VERSION 5.7 ;
  NOWIREEXTENSIONATPIN ON ;
  DIVIDERCHAR "/" ;
  BUSBITCHARS "[]" ;
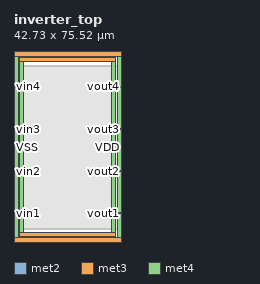
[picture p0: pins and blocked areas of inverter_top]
MACRO inverter_top
  CLASS BLOCK ;
  FOREIGN inverter_top ;
  ORIGIN 0.000 0.000 ;
  SIZE 42.730 BY 75.520 ;
  PIN vin1
    DIRECTION INPUT ;
    USE SIGNAL ;
    ANTENNAGATEAREA 60.000000 ;
    PORT
      LAYER met2 ;
        RECT 0.000 11.250 7.005 11.650 ;
    END
  END vin1
  PIN vout1
    DIRECTION OUTPUT ;
    USE SIGNAL ;
    ANTENNADIFFAREA 9.000000 ;
    PORT
      LAYER met2 ;
        RECT 32.750 11.250 42.730 11.650 ;
    END
  END vout1
  PIN vin2
    DIRECTION INPUT ;
    USE SIGNAL ;
    ANTENNAGATEAREA 60.000000 ;
    PORT
      LAYER met2 ;
        RECT 0.000 27.980 7.005 28.380 ;
    END
  END vin2
  PIN vout2
    DIRECTION OUTPUT ;
    USE SIGNAL ;
    ANTENNADIFFAREA 9.000000 ;
    PORT
      LAYER met2 ;
        RECT 32.750 27.980 42.730 28.380 ;
    END
  END vout2
  PIN vin3
    DIRECTION INPUT ;
    USE SIGNAL ;
    ANTENNAGATEAREA 60.000000 ;
    PORT
      LAYER met2 ;
        RECT 0.000 44.710 7.005 45.110 ;
    END
  END vin3
  PIN vout3
    DIRECTION OUTPUT ;
    USE SIGNAL ;
    ANTENNADIFFAREA 9.000000 ;
    PORT
      LAYER met2 ;
        RECT 32.750 44.710 42.730 45.110 ;
    END
  END vout3
  PIN vin4
    DIRECTION INPUT ;
    USE SIGNAL ;
    ANTENNAGATEAREA 60.000000 ;
    PORT
      LAYER met2 ;
        RECT 0.000 61.440 7.005 61.840 ;
    END
  END vin4
  PIN vout4
    DIRECTION OUTPUT ;
    USE SIGNAL ;
    ANTENNADIFFAREA 9.000000 ;
    PORT
      LAYER met2 ;
        RECT 32.750 61.440 42.730 61.840 ;
    END
  END vout4
  PIN VSS
    DIRECTION INOUT ;
    USE GROUND ;
    ANTENNAGATEAREA 8.000000 ;
    ANTENNADIFFAREA 103.289597 ;
    PORT
      LAYER met3 ;
        RECT 0.000 0.000 42.730 1.600 ;
    END
    PORT
      LAYER met3 ;
        RECT 0.000 73.920 42.730 75.520 ;
    END
    PORT
      LAYER met4 ;
        RECT 0.000 0.000 1.600 75.520 ;
    END
    PORT
      LAYER met4 ;
        RECT 41.130 0.000 42.730 75.520 ;
    END
  END VSS
  PIN VDD
    DIRECTION INOUT ;
    USE POWER ;
    ANTENNAGATEAREA 16.000000 ;
    ANTENNADIFFAREA 124.497597 ;
    PORT
      LAYER met3 ;
        RECT 2.200 2.200 40.530 3.800 ;
    END
    PORT
      LAYER met3 ;
        RECT 2.200 71.720 40.530 73.320 ;
    END
    PORT
      LAYER met4 ;
        RECT 2.200 2.200 3.800 73.320 ;
    END
    PORT
      LAYER met4 ;
        RECT 38.930 2.200 40.530 73.320 ;
    END
  END VDD
  OBS
      LAYER nwell ;
        RECT 4.970 4.780 37.530 70.320 ;
      LAYER li1 ;
        RECT 5.210 4.910 37.290 70.080 ;
      LAYER met1 ;
        RECT 0.100 4.910 42.630 70.080 ;
      LAYER met2 ;
        RECT 0.200 62.120 42.530 69.690 ;
        RECT 7.285 61.160 32.470 62.120 ;
        RECT 0.200 45.390 42.530 61.160 ;
        RECT 7.285 44.430 32.470 45.390 ;
        RECT 0.200 28.660 42.530 44.430 ;
        RECT 7.285 27.700 32.470 28.660 ;
        RECT 0.200 11.930 42.530 27.700 ;
        RECT 7.285 10.970 32.470 11.930 ;
        RECT 0.200 5.300 42.530 10.970 ;
      LAYER met3 ;
        RECT 0.200 5.300 42.530 69.690 ;
  END
END inverter_top
END LIBRARY

